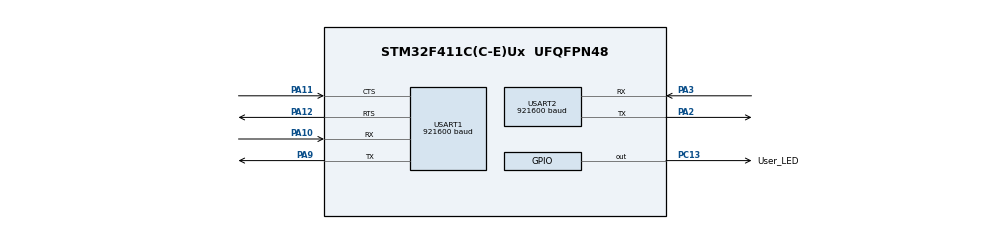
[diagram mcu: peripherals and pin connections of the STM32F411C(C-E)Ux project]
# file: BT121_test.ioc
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Dma.Request0=USART1_TX
Dma.Request1=USART1_RX
Dma.USART1_RX.1.Direction=DMA_PERIPH_TO_MEMORY
Dma.USART1_RX.1.FIFOMode=DMA_FIFOMODE_DISABLE
Dma.USART1_RX.1.Instance=DMA2_Stream2
Dma.USART1_RX.1.MemDataAlignment=DMA_MDATAALIGN_BYTE
Dma.USART1_RX.1.MemInc=DMA_MINC_ENABLE
Dma.USART1_RX.1.Mode=DMA_NORMAL
Dma.USART1_RX.1.PeriphDataAlignment=DMA_PDATAALIGN_BYTE
Dma.USART1_RX.1.PeriphInc=DMA_PINC_DISABLE
Dma.USART1_RX.1.Priority=DMA_PRIORITY_LOW
Dma.USART1_TX.0.Direction=DMA_MEMORY_TO_PERIPH
Dma.USART1_TX.0.FIFOMode=DMA_FIFOMODE_DISABLE
Dma.USART1_TX.0.Instance=DMA2_Stream7
Dma.USART1_TX.0.MemDataAlignment=DMA_MDATAALIGN_BYTE
Dma.USART1_TX.0.MemInc=DMA_MINC_ENABLE
Dma.USART1_TX.0.Mode=DMA_NORMAL
Dma.USART1_TX.0.PeriphDataAlignment=DMA_PDATAALIGN_BYTE
Dma.USART1_TX.0.PeriphInc=DMA_PINC_DISABLE
Dma.USART1_TX.0.Priority=DMA_PRIORITY_LOW
Mcu.Family=STM32F4
Mcu.Name=STM32F411C(C-E)Ux
Mcu.Package=UFQFPN48
NVIC.DMA2_Stream2_IRQn=true\:6\:0\:true\:false\:true\:false\:true\:true
NVIC.DMA2_Stream7_IRQn=true\:6\:0\:true\:false\:true\:false\:true\:true
NVIC.PriorityGroup=NVIC_PRIORITYGROUP_4
NVIC.USART1_IRQn=true\:5\:0\:true\:false\:true\:true\:true\:true
PA10.Mode=Asynchronous
PA10.Signal=USART1_RX
PA11.Mode=CTS_RTS
PA11.Signal=USART1_CTS
PA12.Mode=CTS_RTS
PA12.Signal=USART1_RTS
PA13.Mode=Serial_Wire
PA13.Signal=SYS_JTMS-SWDIO
PA14.Mode=Serial_Wire
PA14.Signal=SYS_JTCK-SWCLK
PA2.Mode=Asynchronous
PA2.Signal=USART2_TX
PA3.Mode=Asynchronous
PA3.Signal=USART2_RX
PA9.Mode=Asynchronous
PA9.Signal=USART1_TX
PC13-ANTI_TAMP.GPIO_Label=User_LED
PC13-ANTI_TAMP.Signal=GPIO_Output
PH0\ -\ OSC_IN.Mode=HSE-External-Oscillator
PH0\ -\ OSC_IN.Signal=RCC_OSC_IN
PH1\ -\ OSC_OUT.Mode=HSE-External-Oscillator
PH1\ -\ OSC_OUT.Signal=RCC_OSC_OUT
ProjectManager.HeapSize=0x200
ProjectManager.StackSize=0x400
ProjectManager.TargetToolchain=STM32CubeIDE
RCC.48MHZClocksFreq_Value=50000000
RCC.AHBFreq_Value=100000000
RCC.APB1CLKDivider=RCC_HCLK_DIV2
RCC.APB1Freq_Value=50000000
RCC.APB1TimFreq_Value=100000000
RCC.APB2Freq_Value=100000000
RCC.APB2TimFreq_Value=100000000
RCC.CortexFreq_Value=100000000
RCC.HCLKFreq_Value=100000000
RCC.HSE_VALUE=25000000
RCC.HSI_VALUE=16000000
RCC.LSE_VALUE=32768
RCC.PLLM=12
RCC.PLLN=96
RCC.PLLSourceVirtual=RCC_PLLSOURCE_HSE
RCC.SYSCLKFreq_VALUE=100000000
RCC.SYSCLKSource=RCC_SYSCLKSOURCE_PLLCLK
RCC.VCOOutputFreq_Value=200000000
USART1.BaudRate=921600
USART1.VirtualMode=VM_ASYNC
USART2.BaudRate=921600
USART2.VirtualMode=VM_ASYNC
board=custom

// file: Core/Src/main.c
/* USER CODE BEGIN Header */
/**
  ******************************************************************************
  * @file           : main.c
  * @brief          : Main program body
  ******************************************************************************
  * @attention
  *
  * Copyright (c) 2022 STMicroelectronics.
  * All rights reserved.
  *
  * This software is licensed under terms that can be found in the LICENSE file
  * in the root directory of this software component.
  * If no LICENSE file comes with this software, it is provided AS-IS.
  *
  ******************************************************************************
  */
/* USER CODE END Header */
#include "main.h"
#include "dma.h"
#include "usart.h"
#include "gpio.h"

/* USER CODE BEGIN Includes */
#include "retarget.h"
#include "dumo_bglib.h"
/* USER CODE END Includes */

/* USER CODE BEGIN PTD */
#define AMOUNT_TO_SEND (1 * (250*4 * 50*4) )
/* USER CODE END PTD */

/* USER CODE BEGIN PV */
BGLIB_DEFINE();

char tmpbaud[10];
/** Variable for storing function return values. */
int ret;
/** Pointer to wifi packet*/
struct dumo_cmd_packet* pck;
/** Buffer for storing data from the serial port. */
static unsigned char buffer[BGLIB_MSG_MAXLEN];
/** Length of message payload data. */
uint16_t msg_length;

unsigned int amount_to_send;
uint8_t ep;
uint32_t frequency;        // ticks per second
uint32_t t1, t2;           // ticks
double elapsedTime;

uint8_t UartTxClp = 1;
/* USER CODE END PV */

void SystemClock_Config(void);

/* USER CODE BEGIN 0 */
/**
 * Function called when a message needs to be written to the serial port.
 * @param msg_len Length of the message.
 * @param msg_data Message data, including the header.
 * @param data_len Optional variable data length.
 * @param data Optional variable data.
 */
uint8_t dataframe[300];
uint8_t length;
static void on_message_send(uint8 msg_len, uint8* msg_data, uint16 data_len, uint8* data)
{
    /*1- polling可以使用*/
//    HAL_UART_Transmit(&huart1, msg_data, msg_len, 0xFF);
//    if(data_len && data)
//    {
//        HAL_UART_Transmit(&huart1, data, data_len, 0xFF);
//    }
    /*2- polling 合并可以使用*/
//    for (int i = 0; i < msg_len; i++) {
//        dataframe[i] = *msg_data++;
//    }
//    if(data_len && data)
//    {
//        for (int i = 0; i < data_len; i++) {
//            dataframe[msg_len + i] = *data++;
//        }
//        HAL_UART_Transmit(&huart1, dataframe, msg_len + data_len, 0xFF);
//    }
//    else{
//        HAL_UART_Transmit(&huart1, dataframe, msg_len , 0xFF);
//    }

    /*3- DMA 合并可以使用*/
    for (int i = 0; i < msg_len; i++) {
        dataframe[i] = *msg_data++;
    }
    if(data_len && data)
    {
        for (int i = 0; i < data_len; i++) {
            dataframe[msg_len + i] = *data++;
        }
        if(UartTxClp){
            UartTxClp = 0;
            HAL_UART_Transmit_DMA(&huart1, dataframe, msg_len + data_len);
        }
    }
    else{
        if(UartTxClp){
            UartTxClp = 0;
            HAL_UART_Transmit_DMA(&huart1, dataframe, msg_len);
        }
    }

}
// Function for printing out the Bluetooth address **initially used for debugging purposes
void print_address(uint8_t address[6]){
    printf("%02x:%02x:%02x:%02x:%02x:%02x", address[5],address[4],address[3],address[2],address[1],address[0]);
}
/**
* Send one frame of data
*/
uint8_t send_index;
void send_one_frame(uint8_t ep, unsigned int amount, unsigned int counter)
{
    uint8_t frame[256];

    if (amount > 250) return; // max frame size

//    frame[0] = send_index++;
    for (unsigned int i = 0; i < amount; i++){
        frame[i] = (uint8_t) i;
    }
    dumo_cmd_endpoint_send(ep, amount, (void *) frame);
}
/* USER CODE END 0 */

int main(void)
{

  /* MCU Configuration--------------------------------------------------------*/

  /* Reset of all peripherals, Initializes the Flash interface and the Systick. */
  HAL_Init();

  /* Configure the system clock */
  SystemClock_Config();

  /* Initialize all configured peripherals */
  MX_GPIO_Init();
  MX_DMA_Init();
  MX_USART2_UART_Init();
  MX_USART1_UART_Init();
  /* USER CODE BEGIN 2 */
  /*注册重定向的串口�???*/
  RetargetInit(&huart2);
  BGLIB_INITIALIZE(on_message_send);

    dumo_cmd_system_hello();

    unsigned int data_counter = 0;
    int flag_full = 0;
  /* USER CODE END 2 */

  /* Infinite loop */
  while (1)
  {

    /* USER CODE BEGIN 3 */
      /**
   * Read enough data from serial port for the BGAPI message header.
   */
      HAL_UART_Receive(&huart1, buffer, BGLIB_MSG_HEADER_LEN, 0xFF);
      /**
       * The buffer now contains the message header. See BGAPI protocol definition for details on packet format.
       */
      msg_length = BGLIB_MSG_LEN(buffer);
      /**
       * Read the payload data if required and store it after the header.
       */
      if(msg_length)
      {
          HAL_UART_Receive(&huart1, &buffer[BGLIB_MSG_HEADER_LEN], msg_length, 0xFF);
      }

      pck= BGLIB_MSG(buffer);

      unsigned int frame_size = 250;

      switch(BGLIB_MSG_ID(buffer))
      {

          case dumo_rsp_system_hello_id:
              printf("Hello from BG\r\n");
              dumo_cmd_system_reset(0);
              break;
          case dumo_evt_system_boot_id:
              printf("Rebooting\r\n");
              break;
          case dumo_evt_system_initialized_id:
              printf("Initializing System address: ");
              print_address(pck->evt_system_initialized.address.addr);
              printf("\r\n");

              /*start rfcomm server, use id 2 for sdp entry*/
              dumo_cmd_bt_rfcomm_start_server(2,0);
              break;
          case dumo_rsp_bt_rfcomm_start_server_id:
              if (pck->rsp_bt_rfcomm_start_server.result == 0)
              {
                  printf("SPP server started; ");
                  printf("Setting discoverable, connectable & bondable on\n");
                  /*Set Bluetooth BR/EDR mode to connectable*/
                  dumo_cmd_bt_gap_set_mode(1, 1, 0);
              }
              else
              {
                  printf("SPP server start failed, errorcode %d\n", pck->rsp_bt_rfcomm_start_server.result);
              }
              break;
          case dumo_rsp_bt_gap_set_mode_id:
              if (pck->rsp_bt_gap_set_mode.result == 0)
              {
                  /*Set bondable mode*/
                  printf("Set bondable mode\n");
                  dumo_cmd_sm_set_bondable_mode(1);
              }
              break;
          case dumo_rsp_sm_set_bondable_mode_id:
              if (pck->rsp_sm_set_bondable_mode.result == 0)
              {
                  printf("Waiting for connection...\n");
              }
              break;
          case dumo_evt_sm_bonded_id:
              if (pck->evt_sm_bonded.bonding != 0xff) dumo_cmd_sm_read_bonding(pck->evt_sm_bonded.bonding);
              break;
          case dumo_rsp_sm_read_bonding_id:
              printf("Bonding from ");
              print_address(pck->rsp_sm_read_bonding.address.addr);
              printf(" succesful\n");
              break;
          case dumo_evt_bt_rfcomm_opened_id:
              printf("SPP connection from ");
              print_address(pck->evt_bt_rfcomm_opened.address.addr);
              printf(" at endpoint %d\n",pck->evt_bt_rfcomm_opened.endpoint);
              ep = pck->evt_bt_rfcomm_opened.endpoint;
              amount_to_send = AMOUNT_TO_SEND;
              // start timer
              printf("BT CONNECT\r\n");
              elapsedTime = HAL_GetTick();
              send_one_frame(ep, frame_size, data_counter);
              break;
          case dumo_rsp_endpoint_send_id:
              if (pck->rsp_endpoint_send.result == 0)
              {
                  amount_to_send -= frame_size;
                  data_counter += frame_size;
//                  printf(".");
//                  if (amount_to_send % 10000 == 0) printf("Amount left %d\n", amount_to_send);
                  if (amount_to_send)
                  {
                      if (frame_size > amount_to_send) frame_size = amount_to_send;
                      send_one_frame(ep, frame_size, data_counter);
                  }
                  else
                  {
                      // compute elapsed time in millisec
                      elapsedTime = HAL_GetTick()-elapsedTime;
                      double speed ;
                      speed = (double) AMOUNT_TO_SEND / elapsedTime *1000.;
                      printf("Sending Speed  %7.0f bytes/second\n", speed);
                      /* Wait for data to finish transfering over the BT link before closing connection */
//                      HAL_Delay(500);
//                      dumo_cmd_endpoint_close(ep);
                      //start timer again
                      amount_to_send = AMOUNT_TO_SEND;
                      frame_size = 250;
                      elapsedTime = HAL_GetTick();
                      send_one_frame(ep, frame_size, data_counter);

                  }
              }
              else if (pck->rsp_endpoint_send.result == dumo_err_buffers_full)
              {
                  /* BT121 buffers are full -> wait for endpoint status that indicates there's free space */
                  flag_full = 1;
                  printf("P");
              }
              else printf("err %d\n", pck->rsp_endpoint_send.result);
              break;
          case dumo_evt_endpoint_status_id:
              if (flag_full && !(pck->evt_endpoint_status.flags & ENDPOINT_FLAG_FULL))
              {
                  /* Free space in endpoint -> continue transfer */
                  printf("C");
                  flag_full = 0;
                  if (amount_to_send)
                  {
                      if (frame_size > amount_to_send) frame_size = amount_to_send;
                      send_one_frame(ep, frame_size, data_counter);
                  }
              }
              else if (flag_full && (pck->evt_endpoint_status.flags & ENDPOINT_FLAG_FULL))
              {
                  // Endpoint full, do nothing
                  printf("F");
              }
              else
              {
                  printf("Endpoint status:%x %x\n", pck->evt_endpoint_status.flags, flag_full);
              }
              break;
          case dumo_evt_endpoint_data_id:
              printf("Received data from endpoint %d ", pck->evt_endpoint_data.endpoint);
              printf("\"");
              {
                  int n;
                  char *c = pck->evt_endpoint_data.data.data;
                  for (n = 0; n < pck->evt_endpoint_data.data.len;n++)
                  {
                      printf("%c",*c++);
                  }
              }
              printf("\"\n");
              /*Echo*/
              {
                  char tmp[100];
                  sprintf(tmp, "Received %d bytes\n", pck->evt_endpoint_data.data.len);
                  dumo_cmd_endpoint_send(pck->evt_endpoint_data.endpoint, strlen(tmp), tmp);
              }

              break;
          case dumo_evt_endpoint_closing_id:
              printf("Closing endpoint:%d\n", pck->evt_endpoint_closing.endpoint);
              printf("BT DISCONNECT\r\n");
              /*endpoint is closing, could check for reason here and then close it*/
              dumo_cmd_endpoint_close(pck->evt_endpoint_closing.endpoint);
              break;
          case dumo_rsp_endpoint_close_id:
              if (pck->rsp_endpoint_close.result == 0)
              {
                  /* Finished */
                  printf("lzx:endpoint_closed\n");
              }
              break;
      }
      memset(&buffer, 0 , sizeof(buffer));

  }
  /* USER CODE END 3 */
}

void SystemClock_Config(void)
{
  RCC_OscInitTypeDef RCC_OscInitStruct = {0};
  RCC_ClkInitTypeDef RCC_ClkInitStruct = {0};

  /** Configure the main internal regulator output voltage
  */
  __HAL_RCC_PWR_CLK_ENABLE();
  __HAL_PWR_VOLTAGESCALING_CONFIG(PWR_REGULATOR_VOLTAGE_SCALE1);
    //先将时钟源选择为内部时钟
    RCC_ClkInitStruct.ClockType = RCC_CLOCKTYPE_SYSCLK;
    RCC_ClkInitStruct.SYSCLKSource = RCC_SYSCLKSOURCE_HSI;
    if (HAL_RCC_ClockConfig(&RCC_ClkInitStruct, FLASH_LATENCY_5) != HAL_OK)
    {
        Error_Handler();
    }
  /** Initializes the RCC Oscillators according to the specified parameters
  * in the RCC_OscInitTypeDef structure.
  */
  RCC_OscInitStruct.OscillatorType = RCC_OSCILLATORTYPE_HSE;
  RCC_OscInitStruct.HSEState = RCC_HSE_ON;
  RCC_OscInitStruct.PLL.PLLState = RCC_PLL_ON;
  RCC_OscInitStruct.PLL.PLLSource = RCC_PLLSOURCE_HSE;
  RCC_OscInitStruct.PLL.PLLM = 12;
  RCC_OscInitStruct.PLL.PLLN = 96;
  RCC_OscInitStruct.PLL.PLLP = RCC_PLLP_DIV2;
  RCC_OscInitStruct.PLL.PLLQ = 4;
  if (HAL_RCC_OscConfig(&RCC_OscInitStruct) != HAL_OK)
  {
    Error_Handler();
  }

  /** Initializes the CPU, AHB and APB buses clocks
  */
  RCC_ClkInitStruct.ClockType = RCC_CLOCKTYPE_HCLK|RCC_CLOCKTYPE_SYSCLK
                              |RCC_CLOCKTYPE_PCLK1|RCC_CLOCKTYPE_PCLK2;
  RCC_ClkInitStruct.SYSCLKSource = RCC_SYSCLKSOURCE_PLLCLK;
  RCC_ClkInitStruct.AHBCLKDivider = RCC_SYSCLK_DIV1;
  RCC_ClkInitStruct.APB1CLKDivider = RCC_HCLK_DIV2;
  RCC_ClkInitStruct.APB2CLKDivider = RCC_HCLK_DIV1;

  if (HAL_RCC_ClockConfig(&RCC_ClkInitStruct, FLASH_LATENCY_3) != HAL_OK)
  {
    Error_Handler();
  }
}

/* USER CODE BEGIN 4 */
void HAL_UART_RxCpltCallback(UART_HandleTypeDef *huart)
{

}

void HAL_UART_TxCpltCallback(UART_HandleTypeDef *huart)
{
    /* Set transmission flag: transfer complete*/
    if(huart->Instance == USART1) {
        UartTxClp = 1;
    }

}

////先将时钟源选择为内部时钟
//RCC_ClkInitStruct.ClockType = RCC_CLOCKTYPE_SYSCLK;
//RCC_ClkInitStruct.SYSCLKSource = RCC_SYSCLKSOURCE_HSI;
//if (HAL_RCC_ClockConfig(&RCC_ClkInitStruct, FLASH_LATENCY_5) != HAL_OK)
//{
//      Error_Handler();
//}
/* USER CODE END 4 */

void Error_Handler(void)
{
  __disable_irq();
  while (1)
  {
  }
}
